VERSION 5.7 ;
  NOWIREEXTENSIONATPIN ON ;
  DIVIDERCHAR "/" ;
  BUSBITCHARS "[]" ;
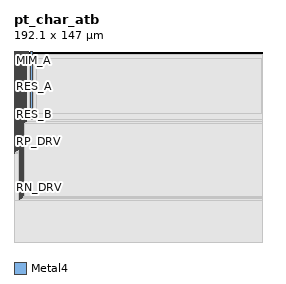
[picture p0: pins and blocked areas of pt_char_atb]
MACRO pt_char_atb
  CLASS BLOCK ;
  FOREIGN pt_char_atb ;
  ORIGIN 16.500 -0.800 ;
  SIZE 192.100 BY 147.000 ;
  PIN RN_LNA
    ANTENNAGATEAREA 5.000000 ;
    ANTENNADIFFAREA 4.400000 ;
    PORT
      LAYER Metal4 ;
        RECT -10.400 35.400 -10.000 147.800 ;
    END
  END RN_LNA
  PIN RP_LNA
    ANTENNADIFFAREA 18.425600 ;
    PORT
      LAYER Metal4 ;
        RECT -14.400 71.560 -14.000 147.800 ;
    END
  END RP_LNA
  PIN RN_MIX
    ANTENNAGATEAREA 2.800000 ;
    ANTENNADIFFAREA 4.400000 ;
    PORT
      LAYER Metal4 ;
        RECT -11.400 34.400 -11.000 147.800 ;
    END
  END RN_MIX
  PIN RP_MIX
    ANTENNADIFFAREA 27.131199 ;
    PORT
      LAYER Metal4 ;
        RECT -15.400 70.560 -15.000 147.800 ;
    END
  END RP_MIX
  PIN RN_SMP
    ANTENNAGATEAREA 2.240000 ;
    ANTENNADIFFAREA 3.520000 ;
    PORT
      LAYER Metal4 ;
        RECT -12.400 33.400 -12.000 147.800 ;
    END
  END RN_SMP
  PIN RP_SMP
    ANTENNADIFFAREA 15.012799 ;
    PORT
      LAYER Metal4 ;
        RECT -16.400 69.560 -16.000 147.800 ;
    END
  END RP_SMP
  PIN RN_DRV
    ANTENNAGATEAREA 10.000000 ;
    ANTENNADIFFAREA 8.800000 ;
    PORT
      LAYER Metal4 ;
        RECT -9.400 36.400 -9.000 147.800 ;
    END
  END RN_DRV
  PIN RP_DRV
    ANTENNADIFFAREA 26.612799 ;
    PORT
      LAYER Metal4 ;
        RECT -13.400 72.560 -13.000 147.800 ;
    END
  END RP_DRV
  PIN RES_A
    PORT
      LAYER Metal4 ;
        RECT -7.400 94.140 -7.000 147.800 ;
    END
  END RES_A
  PIN RES_B
    PORT
      LAYER Metal4 ;
        RECT -8.400 93.140 -8.000 147.800 ;
    END
  END RES_B
  PIN MIM_A
    PORT
      LAYER Metal4 ;
        RECT -5.400 145.540 -5.000 147.800 ;
    END
  END MIM_A
  PIN MIM_B
    PORT
      LAYER Metal4 ;
        RECT -6.400 144.540 -6.000 147.800 ;
    END
  END MIM_B
  PIN VSS
    USE GROUND ;
    PORT
      LAYER Metal4 ;
        RECT -4.000 95.940 -2.000 147.800 ;
    END
  END VSS
  OBS
      LAYER Nwell ;
        RECT 0.000 8.400 48.880 91.300 ;
      LAYER Metal1 ;
        RECT 0.185 8.510 48.695 91.115 ;
      LAYER Metal2 ;
        RECT 0.335 0.900 154.000 145.600 ;
      LAYER Metal3 ;
        RECT -16.500 0.900 154.100 145.600 ;
      LAYER Metal4 ;
        RECT -4.700 145.240 -4.300 145.540 ;
        RECT -5.700 144.240 -4.300 145.240 ;
        RECT -6.700 95.640 -4.300 144.240 ;
        RECT -1.700 95.640 175.600 145.540 ;
        RECT -6.700 93.840 175.600 95.640 ;
        RECT -7.700 92.840 175.600 93.840 ;
        RECT -13.700 71.260 -12.700 72.260 ;
        RECT -14.700 70.260 -12.700 71.260 ;
        RECT -15.700 69.260 -12.700 70.260 ;
        RECT -16.400 33.100 -12.700 69.260 ;
        RECT -8.700 36.100 175.600 92.840 ;
        RECT -9.700 35.100 175.600 36.100 ;
        RECT -10.700 34.100 175.600 35.100 ;
        RECT -11.700 33.100 175.600 34.100 ;
        RECT -16.400 0.800 175.600 33.100 ;
      LAYER Metal5 ;
        RECT 1.000 99.885 175.290 142.620 ;
  END
END pt_char_atb
END LIBRARY

